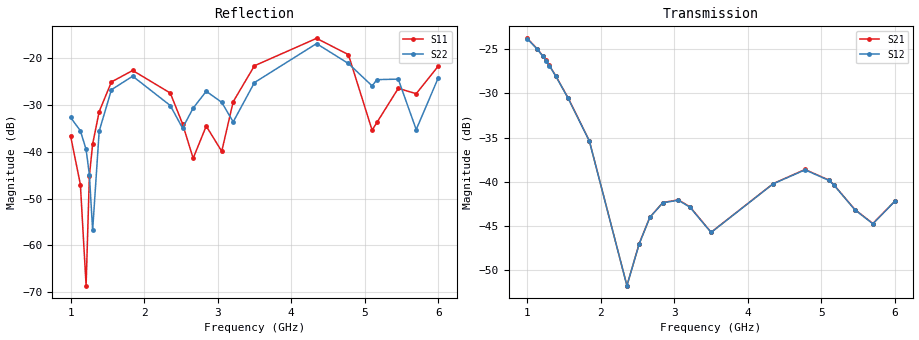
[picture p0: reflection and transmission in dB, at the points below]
!Agilent Technologies,E8364B,MY43040528,A.07.50.67
!Agilent E8364B: A.07.50.67
!Date: Sunday, March 01, 2026 23:00:37
!Correction: S11(Full 2 Port(1,2))
!S21(Full 2 Port(1,2))
!S12(Full 2 Port(1,2))
!S22(Full 2 Port(1,2))
!S2P File: Measurements: S11, S21, S12, S22:
# Hz S  dB  R 50
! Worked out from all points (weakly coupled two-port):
!   451 points, 1 GHz to 6 GHz, reference 50 ohm
!   highest |S21| = -23.76 dB at 1 GHz (marker M1); lowest = -51.8 dB at 2.356 GHz (marker M2)
!   lowest |S11| = -68.6 dB at 1.211 GHz (marker M3), VSWR 1.00, Z = 50 - j0.0122 ohm
!   |S11| at or under -10 dB: start of sweep to end of sweep
!   |S22| runs from -56.8 to -16.9 dB; largest |S21 - S12| = 0.00026
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1e9  -36.60 16.3  -23.76 154.9  -23.80 154.9  -32.66 -13.1
1.133333e9  -47.00 17.4  -24.93 78.8  -24.96 78.8  -35.52 -18.9
1.211111e9  -68.62 -160.7  -25.74 34.6  -25.77 34.6  -39.51 -28.2
1.255556e9  -45.21 -159.9  -26.26 9.4  -26.29 9.4  -44.88 -46.4
1.3e9  -38.35 -164.4  -26.81 -15.6  -26.84 -15.6  -56.79 -154.7
1.388889e9  -31.42 176.4  -28.03 -65.0  -28.05 -65.0  -35.60 113.4
1.555556e9  -25.08 136.5  -30.50 -155.3  -30.54 -155.4  -26.75 63.5
1.844444e9  -22.63 76.6  -35.36 51.1  -35.39 51.2  -23.85 -8.7
2.355556e9  -27.45 0.1  -51.76 -148.9  -51.77 -149.0  -30.12 -93.8
2.522222e9  -34.01 -21.3  -47.00 171.9  -47.05 172.0  -34.94 -81.0
2.666667e9  -41.41 40.7  -44.02 104.1  -44.04 104.2  -30.68 -64.3
2.844444e9  -34.51 49.3  -42.35 12.9  -42.37 12.9  -27.08 -97.3
3.055556e9  -39.90 80.4  -42.05 -97.7  -42.10 -97.7  -29.44 -138.9
3.211111e9  -29.31 109.4  -42.83 -178.1  -42.87 -178.1  -33.62 -124.2
3.5e9  -21.63 63.6  -45.72 46.4  -45.74 46.5  -25.22 -129.9
4.344444e9  -15.77 -41.6  -40.21 23.8  -40.23 23.9  -16.89 111.5
4.777778e9  -19.24 -115.8  -38.61 142.9  -38.65 142.9  -21.14 31.9
5.1e9  -35.39 -120.9  -39.80 -46.8  -39.84 -46.8  -25.92 37.5
5.166667e9  -33.72 -73.2  -40.32 -87.0  -40.34 -87.1  -24.59 34.2
5.455556e9  -26.46 -89.3  -43.15 88.7  -43.18 88.6  -24.48 -21.0
5.7e9  -27.59 -76.1  -44.73 -87.5  -44.76 -87.5  -35.27 -13.4
6e9  -21.70 -82.1  -42.18 60.2  -42.20 60.1  -24.19 -4.1
